VERSION 5.8 ;
BUSBITCHARS "[]" ;
DIVIDERCHAR "/" ;
UNITS
    DATABASE MICRONS 1000 ;
END UNITS

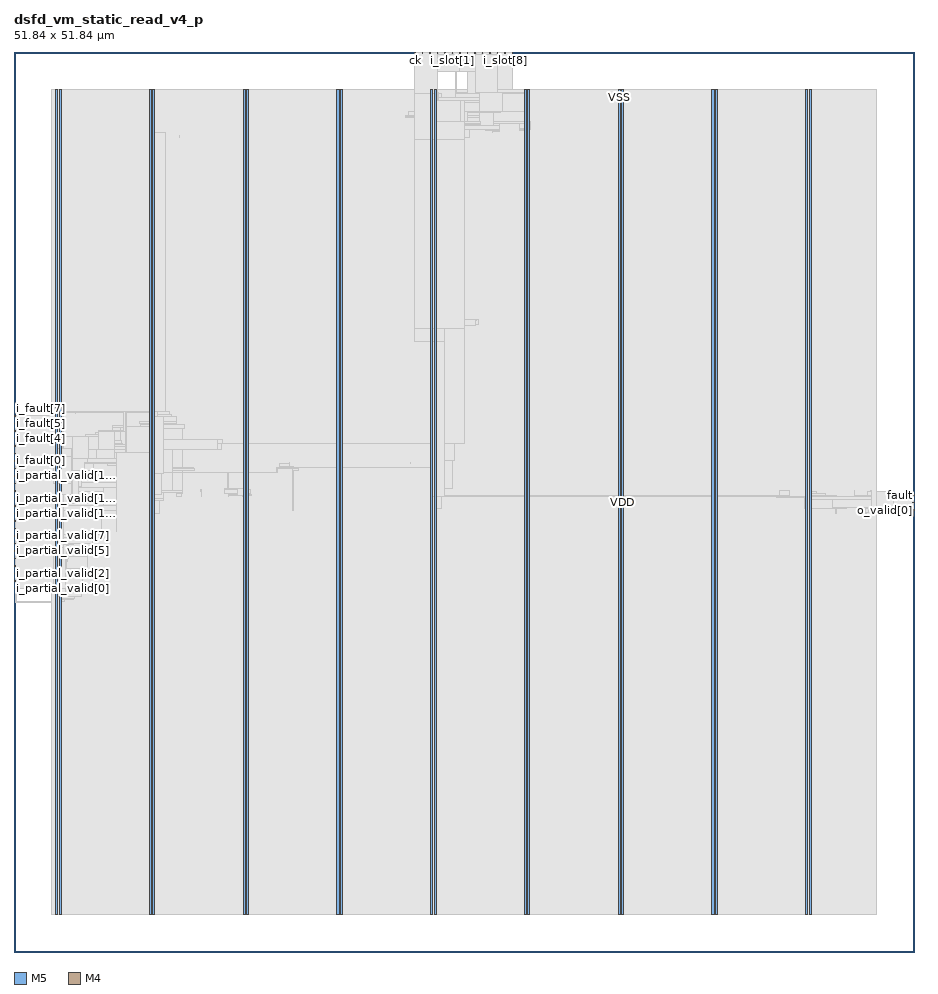
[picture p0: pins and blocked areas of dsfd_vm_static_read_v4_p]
MACRO dsfd_vm_static_read_v4_p
  FOREIGN dsfd_vm_static_read_v4_p 0 0 ;
  CLASS BLOCK ;
  SIZE 51.84 BY 51.84 ;
  PIN ck
    DIRECTION INPUT ;
    USE SIGNAL ;
    PORT
      LAYER M5 ;
        RECT  23.088 51.756 23.112 51.84 ;
    END
  END ck
  PIN fault
    DIRECTION OUTPUT ;
    USE SIGNAL ;
    PORT
      LAYER M4 ;
        RECT  51.756 26.304 51.84 26.328 ;
    END
  END fault
  PIN i_expected[0]
    DIRECTION INPUT ;
    USE SIGNAL ;
    PORT
      LAYER M5 ;
        RECT  23.952 51.756 23.976 51.84 ;
    END
  END i_expected[0]
  PIN i_expected[1]
    DIRECTION INPUT ;
    USE SIGNAL ;
    PORT
      LAYER M5 ;
        RECT  24.384 51.756 24.408 51.84 ;
    END
  END i_expected[1]
  PIN i_fault[0]
    DIRECTION INPUT ;
    USE SIGNAL ;
    PORT
      LAYER M4 ;
        RECT  0 27.84 0.084 27.864 ;
    END
  END i_fault[0]
  PIN i_fault[1]
    DIRECTION INPUT ;
    USE SIGNAL ;
    PORT
      LAYER M4 ;
        RECT  0 28.272 0.084 28.296 ;
    END
  END i_fault[1]
  PIN i_fault[2]
    DIRECTION INPUT ;
    USE SIGNAL ;
    PORT
      LAYER M4 ;
        RECT  0 28.704 0.084 28.728 ;
    END
  END i_fault[2]
  PIN i_fault[3]
    DIRECTION INPUT ;
    USE SIGNAL ;
    PORT
      LAYER M4 ;
        RECT  0 29.136 0.084 29.16 ;
    END
  END i_fault[3]
  PIN i_fault[4]
    DIRECTION INPUT ;
    USE SIGNAL ;
    PORT
      LAYER M4 ;
        RECT  0 29.568 0.084 29.592 ;
    END
  END i_fault[4]
  PIN i_fault[5]
    DIRECTION INPUT ;
    USE SIGNAL ;
    PORT
      LAYER M4 ;
        RECT  0 30 0.084 30.024 ;
    END
  END i_fault[5]
  PIN i_fault[6]
    DIRECTION INPUT ;
    USE SIGNAL ;
    PORT
      LAYER M4 ;
        RECT  0 30.432 0.084 30.456 ;
    END
  END i_fault[6]
  PIN i_fault[7]
    DIRECTION INPUT ;
    USE SIGNAL ;
    PORT
      LAYER M4 ;
        RECT  0 30.864 0.084 30.888 ;
    END
  END i_fault[7]
  PIN i_partial_valid[0]
    DIRECTION INPUT ;
    USE SIGNAL ;
    PORT
      LAYER M4 ;
        RECT  0 20.928 0.084 20.952 ;
    END
  END i_partial_valid[0]
  PIN i_partial_valid[10]
    DIRECTION INPUT ;
    USE SIGNAL ;
    PORT
      LAYER M4 ;
        RECT  0 25.248 0.084 25.272 ;
    END
  END i_partial_valid[10]
  PIN i_partial_valid[11]
    DIRECTION INPUT ;
    USE SIGNAL ;
    PORT
      LAYER M4 ;
        RECT  0 25.68 0.084 25.704 ;
    END
  END i_partial_valid[11]
  PIN i_partial_valid[12]
    DIRECTION INPUT ;
    USE SIGNAL ;
    PORT
      LAYER M4 ;
        RECT  0 26.112 0.084 26.136 ;
    END
  END i_partial_valid[12]
  PIN i_partial_valid[13]
    DIRECTION INPUT ;
    USE SIGNAL ;
    PORT
      LAYER M4 ;
        RECT  0 26.544 0.084 26.568 ;
    END
  END i_partial_valid[13]
  PIN i_partial_valid[14]
    DIRECTION INPUT ;
    USE SIGNAL ;
    PORT
      LAYER M4 ;
        RECT  0 26.976 0.084 27 ;
    END
  END i_partial_valid[14]
  PIN i_partial_valid[15]
    DIRECTION INPUT ;
    USE SIGNAL ;
    PORT
      LAYER M4 ;
        RECT  0 27.408 0.084 27.432 ;
    END
  END i_partial_valid[15]
  PIN i_partial_valid[1]
    DIRECTION INPUT ;
    USE SIGNAL ;
    PORT
      LAYER M4 ;
        RECT  0 21.36 0.084 21.384 ;
    END
  END i_partial_valid[1]
  PIN i_partial_valid[2]
    DIRECTION INPUT ;
    USE SIGNAL ;
    PORT
      LAYER M4 ;
        RECT  0 21.792 0.084 21.816 ;
    END
  END i_partial_valid[2]
  PIN i_partial_valid[3]
    DIRECTION INPUT ;
    USE SIGNAL ;
    PORT
      LAYER M4 ;
        RECT  0 22.224 0.084 22.248 ;
    END
  END i_partial_valid[3]
  PIN i_partial_valid[4]
    DIRECTION INPUT ;
    USE SIGNAL ;
    PORT
      LAYER M4 ;
        RECT  0 22.656 0.084 22.68 ;
    END
  END i_partial_valid[4]
  PIN i_partial_valid[5]
    DIRECTION INPUT ;
    USE SIGNAL ;
    PORT
      LAYER M4 ;
        RECT  0 23.088 0.084 23.112 ;
    END
  END i_partial_valid[5]
  PIN i_partial_valid[6]
    DIRECTION INPUT ;
    USE SIGNAL ;
    PORT
      LAYER M4 ;
        RECT  0 23.52 0.084 23.544 ;
    END
  END i_partial_valid[6]
  PIN i_partial_valid[7]
    DIRECTION INPUT ;
    USE SIGNAL ;
    PORT
      LAYER M4 ;
        RECT  0 23.952 0.084 23.976 ;
    END
  END i_partial_valid[7]
  PIN i_partial_valid[8]
    DIRECTION INPUT ;
    USE SIGNAL ;
    PORT
      LAYER M4 ;
        RECT  0 24.384 0.084 24.408 ;
    END
  END i_partial_valid[8]
  PIN i_partial_valid[9]
    DIRECTION INPUT ;
    USE SIGNAL ;
    PORT
      LAYER M4 ;
        RECT  0 24.816 0.084 24.84 ;
    END
  END i_partial_valid[9]
  PIN i_slot[0]
    DIRECTION INPUT ;
    USE SIGNAL ;
    PORT
      LAYER M5 ;
        RECT  24.816 51.756 24.84 51.84 ;
    END
  END i_slot[0]
  PIN i_slot[1]
    DIRECTION INPUT ;
    USE SIGNAL ;
    PORT
      LAYER M5 ;
        RECT  25.248 51.756 25.272 51.84 ;
    END
  END i_slot[1]
  PIN i_slot[2]
    DIRECTION INPUT ;
    USE SIGNAL ;
    PORT
      LAYER M5 ;
        RECT  25.68 51.756 25.704 51.84 ;
    END
  END i_slot[2]
  PIN i_slot[3]
    DIRECTION INPUT ;
    USE SIGNAL ;
    PORT
      LAYER M5 ;
        RECT  26.112 51.756 26.136 51.84 ;
    END
  END i_slot[3]
  PIN i_slot[4]
    DIRECTION INPUT ;
    USE SIGNAL ;
    PORT
      LAYER M5 ;
        RECT  26.544 51.756 26.568 51.84 ;
    END
  END i_slot[4]
  PIN i_slot[5]
    DIRECTION INPUT ;
    USE SIGNAL ;
    PORT
      LAYER M5 ;
        RECT  26.976 51.756 27 51.84 ;
    END
  END i_slot[5]
  PIN i_slot[6]
    DIRECTION INPUT ;
    USE SIGNAL ;
    PORT
      LAYER M5 ;
        RECT  27.408 51.756 27.432 51.84 ;
    END
  END i_slot[6]
  PIN i_slot[7]
    DIRECTION INPUT ;
    USE SIGNAL ;
    PORT
      LAYER M5 ;
        RECT  27.84 51.756 27.864 51.84 ;
    END
  END i_slot[7]
  PIN i_slot[8]
    DIRECTION INPUT ;
    USE SIGNAL ;
    PORT
      LAYER M5 ;
        RECT  28.272 51.756 28.296 51.84 ;
    END
  END i_slot[8]
  PIN i_slot[9]
    DIRECTION INPUT ;
    USE SIGNAL ;
    PORT
      LAYER M5 ;
        RECT  28.704 51.756 28.728 51.84 ;
    END
  END i_slot[9]
  PIN o_valid[0]
    DIRECTION OUTPUT ;
    USE SIGNAL ;
    PORT
      LAYER M4 ;
        RECT  51.756 25.44 51.84 25.464 ;
    END
  END o_valid[0]
  PIN o_valid[1]
    DIRECTION OUTPUT ;
    USE SIGNAL ;
    PORT
      LAYER M4 ;
        RECT  51.756 25.872 51.84 25.896 ;
    END
  END o_valid[1]
  PIN rst_n
    DIRECTION INPUT ;
    USE SIGNAL ;
    PORT
      LAYER M5 ;
        RECT  23.52 51.756 23.544 51.84 ;
    END
  END rst_n
  PIN VDD
    DIRECTION INOUT ;
    USE POWER ;
    PORT
      LAYER M5 ;
        RECT  45.792 2.151 45.912 49.689 ;
        RECT  40.392 2.151 40.512 49.689 ;
        RECT  34.992 2.151 35.112 49.689 ;
        RECT  29.592 2.151 29.712 49.689 ;
        RECT  24.192 2.151 24.312 49.689 ;
        RECT  18.792 2.151 18.912 49.689 ;
        RECT  13.392 2.151 13.512 49.689 ;
        RECT  7.992 2.151 8.112 49.689 ;
        RECT  2.592 2.151 2.712 49.689 ;
    END
  END VDD
  PIN VSS
    DIRECTION INOUT ;
    USE GROUND ;
    PORT
      LAYER M5 ;
        RECT  45.6 2.137 45.72 49.703 ;
        RECT  40.2 2.137 40.32 49.703 ;
        RECT  34.8 2.137 34.92 49.703 ;
        RECT  29.4 2.137 29.52 49.703 ;
        RECT  24 2.137 24.12 49.703 ;
        RECT  18.6 2.137 18.72 49.703 ;
        RECT  13.2 2.137 13.32 49.703 ;
        RECT  7.8 2.137 7.92 49.703 ;
        RECT  2.4 2.137 2.52 49.703 ;
    END
  END VSS
  # OT_OBS_CLOSED layer=M5 d_um=1.536 added=13
  OBS
    LAYER RVTN ;
     RECT  2.16 2.16 49.68 2.295 ;
     RECT  2.16 2.565 49.68 2.835 ;
     RECT  2.16 3.105 49.68 3.375 ;
     RECT  2.16 3.645 49.68 3.915 ;
     RECT  2.16 4.185 49.68 4.455 ;
     RECT  2.16 4.725 49.68 4.995 ;
     RECT  2.16 5.265 49.68 5.535 ;
     RECT  2.16 5.805 49.68 6.075 ;
     RECT  2.16 6.345 49.68 6.615 ;
     RECT  2.16 6.885 49.68 7.155 ;
     RECT  2.16 7.425 49.68 7.695 ;
     RECT  2.16 7.965 49.68 8.235 ;
     RECT  2.16 8.505 49.68 8.775 ;
     RECT  2.16 9.045 49.68 9.315 ;
     RECT  2.16 9.585 49.68 9.855 ;
     RECT  2.16 10.125 49.68 10.395 ;
     RECT  2.16 10.665 49.68 10.935 ;
     RECT  2.16 11.205 49.68 11.475 ;
     RECT  2.16 11.745 49.68 12.015 ;
     RECT  2.16 12.285 49.68 12.555 ;
     RECT  2.16 12.825 49.68 13.095 ;
     RECT  2.16 13.365 49.68 13.635 ;
     RECT  2.16 13.905 49.68 14.175 ;
     RECT  2.16 14.445 49.68 14.715 ;
     RECT  2.16 14.985 49.68 15.255 ;
     RECT  2.16 15.525 49.68 15.795 ;
     RECT  2.16 16.065 49.68 16.335 ;
     RECT  2.16 16.605 49.68 16.875 ;
     RECT  2.16 17.145 49.68 17.415 ;
     RECT  2.16 17.685 49.68 17.955 ;
     RECT  2.16 18.225 49.68 18.495 ;
     RECT  2.16 18.765 49.68 19.035 ;
     RECT  2.16 19.305 49.68 19.575 ;
     RECT  2.16 19.845 49.68 20.115 ;
     RECT  2.16 20.385 49.68 20.655 ;
     RECT  2.16 20.925 49.68 21.195 ;
     RECT  2.16 21.465 49.68 21.735 ;
     RECT  2.16 22.005 49.68 22.275 ;
     RECT  2.16 22.545 49.68 22.815 ;
     RECT  2.16 23.085 49.68 23.355 ;
     RECT  2.16 23.625 49.68 23.895 ;
     RECT  2.16 24.165 49.68 24.435 ;
     RECT  2.16 24.705 49.68 24.975 ;
     RECT  2.16 25.245 49.68 25.515 ;
     RECT  2.16 25.785 49.68 26.055 ;
     RECT  2.16 26.325 49.68 26.595 ;
     RECT  2.16 26.865 49.68 27.135 ;
     RECT  2.16 27.405 49.68 27.675 ;
     RECT  2.16 27.945 49.68 28.215 ;
     RECT  2.16 28.485 49.68 28.755 ;
     RECT  2.16 29.025 49.68 29.295 ;
     RECT  2.16 29.565 49.68 29.835 ;
     RECT  2.16 30.105 49.68 30.375 ;
     RECT  2.16 30.645 49.68 30.915 ;
     RECT  2.16 31.185 49.68 31.455 ;
     RECT  2.16 31.725 49.68 31.995 ;
     RECT  2.16 32.265 49.68 32.535 ;
     RECT  2.16 32.805 49.68 33.075 ;
     RECT  2.16 33.345 49.68 33.615 ;
     RECT  2.16 33.885 49.68 34.155 ;
     RECT  2.16 34.425 49.68 34.695 ;
     RECT  2.16 34.965 49.68 35.235 ;
     RECT  2.16 35.505 49.68 35.775 ;
     RECT  2.16 36.045 49.68 36.315 ;
     RECT  2.16 36.585 49.68 36.855 ;
     RECT  2.16 37.125 49.68 37.395 ;
     RECT  2.16 37.665 49.68 37.935 ;
     RECT  2.16 38.205 49.68 38.475 ;
     RECT  2.16 38.745 49.68 39.015 ;
     RECT  2.16 39.285 49.68 39.555 ;
     RECT  2.16 39.825 49.68 40.095 ;
     RECT  2.16 40.365 49.68 40.635 ;
     RECT  2.16 40.905 49.68 41.175 ;
     RECT  2.16 41.445 49.68 41.715 ;
     RECT  2.16 41.985 49.68 42.255 ;
     RECT  2.16 42.525 49.68 42.795 ;
     RECT  2.16 43.065 49.68 43.335 ;
     RECT  2.16 43.605 49.68 43.875 ;
     RECT  2.16 44.145 49.68 44.415 ;
     RECT  2.16 44.685 49.68 44.955 ;
     RECT  2.16 45.225 49.68 45.495 ;
     RECT  2.16 45.765 49.68 46.035 ;
     RECT  2.16 46.305 49.68 46.575 ;
     RECT  2.16 46.845 49.68 47.115 ;
     RECT  2.16 47.385 49.68 47.655 ;
     RECT  2.16 47.925 49.68 48.195 ;
     RECT  2.16 48.465 49.68 48.735 ;
     RECT  2.16 49.005 49.68 49.275 ;
     RECT  2.16 49.545 49.68 49.68 ;
    LAYER RVTP ;
     RECT  2.16 2.295 49.68 2.565 ;
     RECT  2.16 2.835 49.68 3.105 ;
     RECT  2.16 3.375 49.68 3.645 ;
     RECT  2.16 3.915 49.68 4.185 ;
     RECT  2.16 4.455 49.68 4.725 ;
     RECT  2.16 4.995 49.68 5.265 ;
     RECT  2.16 5.535 49.68 5.805 ;
     RECT  2.16 6.075 49.68 6.345 ;
     RECT  2.16 6.615 49.68 6.885 ;
     RECT  2.16 7.155 49.68 7.425 ;
     RECT  2.16 7.695 49.68 7.965 ;
     RECT  2.16 8.235 49.68 8.505 ;
     RECT  2.16 8.775 49.68 9.045 ;
     RECT  2.16 9.315 49.68 9.585 ;
     RECT  2.16 9.855 49.68 10.125 ;
     RECT  2.16 10.395 49.68 10.665 ;
     RECT  2.16 10.935 49.68 11.205 ;
     RECT  2.16 11.475 49.68 11.745 ;
     RECT  2.16 12.015 49.68 12.285 ;
     RECT  2.16 12.555 49.68 12.825 ;
     RECT  2.16 13.095 49.68 13.365 ;
     RECT  2.16 13.635 49.68 13.905 ;
     RECT  2.16 14.175 49.68 14.445 ;
     RECT  2.16 14.715 49.68 14.985 ;
     RECT  2.16 15.255 49.68 15.525 ;
     RECT  2.16 15.795 49.68 16.065 ;
     RECT  2.16 16.335 49.68 16.605 ;
     RECT  2.16 16.875 49.68 17.145 ;
     RECT  2.16 17.415 49.68 17.685 ;
     RECT  2.16 17.955 49.68 18.225 ;
     RECT  2.16 18.495 49.68 18.765 ;
     RECT  2.16 19.035 49.68 19.305 ;
     RECT  2.16 19.575 49.68 19.845 ;
     RECT  2.16 20.115 49.68 20.385 ;
     RECT  2.16 20.655 49.68 20.925 ;
     RECT  2.16 21.195 49.68 21.465 ;
     RECT  2.16 21.735 49.68 22.005 ;
     RECT  2.16 22.275 49.68 22.545 ;
     RECT  2.16 22.815 49.68 23.085 ;
     RECT  2.16 23.355 49.68 23.625 ;
     RECT  2.16 23.895 49.68 24.165 ;
     RECT  2.16 24.435 49.68 24.705 ;
     RECT  2.16 24.975 49.68 25.245 ;
     RECT  2.16 25.515 49.68 25.785 ;
     RECT  2.16 26.055 49.68 26.325 ;
     RECT  2.16 26.595 49.68 26.865 ;
     RECT  2.16 27.135 49.68 27.405 ;
     RECT  2.16 27.675 49.68 27.945 ;
     RECT  2.16 28.215 49.68 28.485 ;
     RECT  2.16 28.755 49.68 29.025 ;
     RECT  2.16 29.295 49.68 29.565 ;
     RECT  2.16 29.835 49.68 30.105 ;
     RECT  2.16 30.375 49.68 30.645 ;
     RECT  2.16 30.915 49.68 31.185 ;
     RECT  2.16 31.455 49.68 31.725 ;
     RECT  2.16 31.995 49.68 32.265 ;
     RECT  2.16 32.535 49.68 32.805 ;
     RECT  2.16 33.075 49.68 33.345 ;
     RECT  2.16 33.615 49.68 33.885 ;
     RECT  2.16 34.155 49.68 34.425 ;
     RECT  2.16 34.695 49.68 34.965 ;
     RECT  2.16 35.235 49.68 35.505 ;
     RECT  2.16 35.775 49.68 36.045 ;
     RECT  2.16 36.315 49.68 36.585 ;
     RECT  2.16 36.855 49.68 37.125 ;
     RECT  2.16 37.395 49.68 37.665 ;
     RECT  2.16 37.935 49.68 38.205 ;
     RECT  2.16 38.475 49.68 38.745 ;
     RECT  2.16 39.015 49.68 39.285 ;
     RECT  2.16 39.555 49.68 39.825 ;
     RECT  2.16 40.095 49.68 40.365 ;
     RECT  2.16 40.635 49.68 40.905 ;
     RECT  2.16 41.175 49.68 41.445 ;
     RECT  2.16 41.715 49.68 41.985 ;
     RECT  2.16 42.255 49.68 42.525 ;
     RECT  2.16 42.795 49.68 43.065 ;
     RECT  2.16 43.335 49.68 43.605 ;
     RECT  2.16 43.875 49.68 44.145 ;
     RECT  2.16 44.415 49.68 44.685 ;
     RECT  2.16 44.955 49.68 45.225 ;
     RECT  2.16 45.495 49.68 45.765 ;
     RECT  2.16 46.035 49.68 46.305 ;
     RECT  2.16 46.575 49.68 46.845 ;
     RECT  2.16 47.115 49.68 47.385 ;
     RECT  2.16 47.655 49.68 47.925 ;
     RECT  2.16 48.195 49.68 48.465 ;
     RECT  2.16 48.735 49.68 49.005 ;
     RECT  2.16 49.275 49.68 49.545 ;
    LAYER M1 ;
     RECT  2.16 2.151 49.68 49.689 ;
    LAYER M2 ;
     RECT  0.103 20.16 2.16 20.178 ;
     RECT  0.535 22.086 2.16 22.104 ;
     RECT  2.16 2.151 49.68 49.689 ;
     RECT  49.68 25.452 50.711 26.514 ;
    LAYER M3 ;
     RECT  2.415 2.143 2.505 2.413 ;
     RECT  7.815 2.143 7.905 2.413 ;
     RECT  13.215 2.143 13.305 2.413 ;
     RECT  18.615 2.143 18.705 2.413 ;
     RECT  24.015 2.143 24.105 2.413 ;
     RECT  29.415 2.143 29.505 2.413 ;
     RECT  34.815 2.143 34.905 2.413 ;
     RECT  40.215 2.143 40.305 2.413 ;
     RECT  45.615 2.143 45.705 2.413 ;
     RECT  2.415 2.413 2.697 20.191 ;
     RECT  2.412 20.191 2.898 20.317 ;
     RECT  2.412 20.317 3.402 20.353 ;
     RECT  2.412 20.353 3.51 20.461 ;
     RECT  2.412 20.461 3.906 20.731 ;
     RECT  2.34 20.731 3.906 20.923 ;
     RECT  2.304 20.923 3.906 21.001 ;
     RECT  0.108 20.155 0.126 21.389 ;
     RECT  2.304 21.001 3.942 22.081 ;
     RECT  2.304 22.081 4.23 22.775 ;
     RECT  2.34 22.775 4.23 22.981 ;
     RECT  2.34 22.981 4.374 23.053 ;
     RECT  0.54 22.081 0.558 23.117 ;
     RECT  2.34 23.053 4.482 23.161 ;
     RECT  2.34 23.161 4.518 23.515 ;
     RECT  2.304 23.515 4.518 23.863 ;
     RECT  2.304 23.863 4.95 24.061 ;
     RECT  7.815 2.413 8.097 25.285 ;
     RECT  49.068 25.285 49.086 25.321 ;
     RECT  2.304 24.061 5.058 25.447 ;
     RECT  5.904 24.205 5.922 25.447 ;
     RECT  47.34 25.249 47.358 25.519 ;
     RECT  45.615 2.413 45.897 25.531 ;
     RECT  24.015 2.413 24.297 25.555 ;
     RECT  49.068 25.321 49.194 25.555 ;
     RECT  47.16 25.519 47.97 25.591 ;
     RECT  49.068 25.555 49.374 25.591 ;
     RECT  2.304 25.447 5.922 25.745 ;
     RECT  7.815 25.285 8.37 25.987 ;
     RECT  45.54 25.531 45.897 26.059 ;
     RECT  47.16 25.591 49.374 26.059 ;
     RECT  7.815 25.987 8.586 26.095 ;
     RECT  43.956 26.203 43.974 26.221 ;
     RECT  45.54 26.059 49.374 26.237 ;
     RECT  45.615 26.237 49.374 26.249 ;
     RECT  9.612 26.221 9.63 26.257 ;
     RECT  13.215 2.413 13.497 26.257 ;
     RECT  43.884 26.221 43.974 26.257 ;
     RECT  43.884 26.257 44.658 26.285 ;
     RECT  45.615 26.249 47.394 26.285 ;
     RECT  48.384 26.249 49.374 26.285 ;
     RECT  12.348 26.257 12.366 26.293 ;
     RECT  13.14 26.257 13.497 26.293 ;
     RECT  12.348 26.293 13.662 26.333 ;
     RECT  9.36 26.257 9.63 26.401 ;
     RECT  12.348 26.333 13.626 26.401 ;
     RECT  45.615 26.285 46.746 26.429 ;
     RECT  7.815 26.095 8.622 26.491 ;
     RECT  9.36 26.401 9.702 26.491 ;
     RECT  45.615 26.429 46.206 26.519 ;
     RECT  49.176 26.285 49.374 26.519 ;
     RECT  50.688 25.435 50.706 26.519 ;
     RECT  2.304 25.745 5.13 26.527 ;
     RECT  10.8 26.221 10.818 26.527 ;
     RECT  10.764 26.527 10.818 26.528 ;
     RECT  48.384 26.285 48.402 26.555 ;
     RECT  49.356 26.519 49.374 26.555 ;
     RECT  7.815 26.491 9.702 26.591 ;
     RECT  44.1 26.285 44.658 26.591 ;
     RECT  12.132 26.401 13.626 26.627 ;
     RECT  7.815 26.591 8.37 26.663 ;
     RECT  10.764 26.528 10.782 26.663 ;
     RECT  13.14 26.627 13.626 26.663 ;
     RECT  24.015 25.555 24.606 26.671 ;
     RECT  12.132 26.627 12.366 26.699 ;
     RECT  2.268 26.527 5.13 26.761 ;
     RECT  5.904 25.745 5.922 26.761 ;
     RECT  12.348 26.699 12.366 26.765 ;
     RECT  13.14 26.663 13.497 26.789 ;
     RECT  2.268 26.761 5.922 27.059 ;
     RECT  2.268 27.059 4.842 27.329 ;
     RECT  2.268 27.329 4.59 27.707 ;
     RECT  9.108 26.591 9.702 27.715 ;
     RECT  16.056 25.411 16.074 27.715 ;
     RECT  9.108 27.715 10.314 27.751 ;
     RECT  9.108 27.751 10.422 27.869 ;
     RECT  16.056 27.715 16.398 27.869 ;
     RECT  15.12 27.595 15.138 27.877 ;
     RECT  16.056 27.869 16.074 27.877 ;
     RECT  9.108 27.869 10.314 27.905 ;
     RECT  2.268 27.707 3.294 27.917 ;
     RECT  15.12 27.877 16.074 27.917 ;
     RECT  15.264 27.917 16.074 27.941 ;
     RECT  5.904 27.059 5.922 28.021 ;
     RECT  4.068 27.707 4.59 28.111 ;
     RECT  5.4 28.021 5.922 28.111 ;
     RECT  15.264 27.941 15.858 28.139 ;
     RECT  2.268 27.917 3.222 28.175 ;
     RECT  4.068 28.111 5.922 28.175 ;
     RECT  15.84 28.139 15.858 28.175 ;
     RECT  22.824 28.111 22.842 28.211 ;
     RECT  24.015 26.671 25.254 28.291 ;
     RECT  4.248 28.175 5.922 28.445 ;
     RECT  7.815 26.663 8.097 28.759 ;
     RECT  5.76 28.445 5.922 28.789 ;
     RECT  7.416 28.759 8.097 28.795 ;
     RECT  7.308 28.795 8.097 28.993 ;
     RECT  9.108 27.905 9.702 28.993 ;
     RECT  5.76 28.789 6.462 29.101 ;
     RECT  7.308 28.993 9.702 29.101 ;
     RECT  5.76 29.101 9.702 29.255 ;
     RECT  5.76 29.255 6.246 29.291 ;
     RECT  2.268 28.175 3.186 29.363 ;
     RECT  11.7 28.921 11.97 29.461 ;
     RECT  5.76 29.291 6.21 29.489 ;
     RECT  4.248 28.445 4.734 29.497 ;
     RECT  11.7 29.461 12.006 29.501 ;
     RECT  11.7 29.501 11.718 29.525 ;
     RECT  2.412 29.363 3.186 29.569 ;
     RECT  4.14 29.497 4.734 29.659 ;
     RECT  2.412 29.569 3.33 29.693 ;
     RECT  4.14 29.659 4.878 29.795 ;
     RECT  4.716 29.795 4.878 29.939 ;
     RECT  4.86 29.939 4.878 30.035 ;
     RECT  5.76 29.489 6.138 30.037 ;
     RECT  2.412 29.693 2.697 30.065 ;
     RECT  7.308 29.255 9.702 30.181 ;
     RECT  5.652 30.037 6.138 30.235 ;
     RECT  5.652 30.235 6.354 30.335 ;
     RECT  6.336 30.335 6.354 30.371 ;
     RECT  7.308 30.181 9.846 30.371 ;
     RECT  7.308 30.371 9.702 30.407 ;
     RECT  2.415 30.065 2.697 30.415 ;
     RECT  7.308 30.407 9.378 30.415 ;
     RECT  2.415 30.415 2.826 30.461 ;
     RECT  7.2 30.415 9.378 30.569 ;
     RECT  7.815 30.569 9.378 30.839 ;
     RECT  7.815 30.839 9.054 30.947 ;
     RECT  6.048 31.081 6.066 31.099 ;
     RECT  7.815 30.947 8.946 31.109 ;
     RECT  3.528 30.991 3.546 31.133 ;
     RECT  5.868 31.099 6.066 31.133 ;
     RECT  5.868 31.133 5.886 31.145 ;
     RECT  24.015 28.291 25.362 35.035 ;
     RECT  24.015 35.035 25.938 35.075 ;
     RECT  26.568 36.085 26.586 36.121 ;
     RECT  26.568 36.121 26.766 36.125 ;
     RECT  26.604 36.125 26.766 36.419 ;
     RECT  24.015 35.075 25.362 38.515 ;
     RECT  24.015 38.515 25.578 46.921 ;
     RECT  9.54 46.921 9.558 47.039 ;
     RECT  7.815 31.109 8.73 47.219 ;
     RECT  27.54 47.191 27.558 47.281 ;
     RECT  27.54 47.281 27.954 47.317 ;
     RECT  29.415 2.413 29.697 47.317 ;
     RECT  29.124 47.317 29.697 47.353 ;
     RECT  24.015 46.921 26.262 47.389 ;
     RECT  27.144 47.317 27.954 47.389 ;
     RECT  29.124 47.353 29.754 47.425 ;
     RECT  24.015 47.389 27.954 47.579 ;
     RECT  24.015 47.579 26.874 47.659 ;
     RECT  23.508 47.659 26.874 47.731 ;
     RECT  27.612 47.579 27.954 47.731 ;
     RECT  29.088 47.425 29.754 47.731 ;
     RECT  23.22 47.731 26.874 47.849 ;
     RECT  27.612 47.731 29.754 47.849 ;
     RECT  23.22 47.849 26.838 48.091 ;
     RECT  22.536 48.091 26.838 48.191 ;
     RECT  22.716 48.191 26.838 48.389 ;
     RECT  27.612 47.849 29.697 48.389 ;
     RECT  28.008 48.389 29.697 48.413 ;
     RECT  23.364 48.389 26.838 48.929 ;
     RECT  23.472 48.929 26.838 49.037 ;
     RECT  23.508 49.037 26.838 49.073 ;
     RECT  23.544 49.073 26.838 49.199 ;
     RECT  2.415 30.461 2.697 49.427 ;
     RECT  7.815 47.219 8.097 49.427 ;
     RECT  13.215 26.789 13.497 49.427 ;
     RECT  18.615 2.413 18.897 49.427 ;
     RECT  28.152 48.413 29.697 49.427 ;
     RECT  34.815 2.413 35.097 49.427 ;
     RECT  40.215 2.413 40.497 49.427 ;
     RECT  45.615 26.519 45.897 49.427 ;
     RECT  23.544 49.199 24.642 49.469 ;
     RECT  25.452 49.199 26.802 49.469 ;
     RECT  23.544 49.469 24.462 49.505 ;
     RECT  23.652 49.505 24.462 49.517 ;
     RECT  25.452 49.469 26.622 49.517 ;
     RECT  28.152 49.427 29.505 49.517 ;
     RECT  23.652 49.517 24.105 49.541 ;
     RECT  27.612 49.531 27.63 49.577 ;
     RECT  2.415 49.427 2.505 49.697 ;
     RECT  7.815 49.427 7.905 49.697 ;
     RECT  13.215 49.427 13.305 49.697 ;
     RECT  18.615 49.427 18.705 49.697 ;
     RECT  23.976 49.541 24.105 49.697 ;
     RECT  29.415 49.517 29.505 49.697 ;
     RECT  34.815 49.427 34.905 49.697 ;
     RECT  40.215 49.427 40.305 49.697 ;
     RECT  45.615 49.427 45.705 49.697 ;
     RECT  23.976 49.697 23.994 49.853 ;
     RECT  25.452 49.517 25.47 50.765 ;
    LAYER M4 ;
     RECT  0.06 20.928 2.408 30.888 ;
     RECT  2.408 2.148 2.512 49.692 ;
     RECT  2.512 2.418 2.704 49.422 ;
     RECT  2.704 21.936 2.819 24.648 ;
     RECT  2.704 25.728 2.819 31.128 ;
     RECT  2.819 25.824 2.837 31.128 ;
     RECT  2.819 24.624 2.867 24.648 ;
     RECT  2.704 20.496 2.963 20.52 ;
     RECT  2.819 21.936 3.004 23.496 ;
     RECT  3.004 22.512 3.089 23.496 ;
     RECT  3.089 22.656 3.125 23.496 ;
     RECT  2.837 25.824 3.347 29.688 ;
     RECT  3.125 23.472 3.413 23.496 ;
     RECT  3.347 25.824 3.737 27.192 ;
     RECT  3.737 26.832 3.881 27.192 ;
     RECT  3.881 27.168 3.989 27.192 ;
     RECT  3.347 28.416 4.277 29.688 ;
     RECT  3.737 25.824 4.493 25.848 ;
     RECT  4.277 28.944 4.849 29.688 ;
     RECT  4.849 28.944 4.889 30.024 ;
     RECT  4.889 30 6.325 30.024 ;
     RECT  2.837 31.104 6.325 31.128 ;
     RECT  4.889 28.944 6.421 28.968 ;
     RECT  6.325 30 6.421 31.128 ;
     RECT  6.421 28.8 6.467 31.128 ;
     RECT  6.467 28.8 6.508 29.352 ;
     RECT  6.508 28.944 7.808 29.352 ;
     RECT  6.467 31.104 7.808 31.128 ;
     RECT  7.808 2.148 7.912 49.692 ;
     RECT  7.912 2.418 8.104 49.422 ;
     RECT  8.104 28.944 8.273 31.128 ;
     RECT  8.104 26.352 8.483 26.376 ;
     RECT  8.273 28.944 8.627 30.84 ;
     RECT  8.627 28.944 11.729 29.496 ;
     RECT  11.729 29.28 12.017 29.496 ;
     RECT  8.104 27.6 12.293 27.624 ;
     RECT  12.293 26.736 12.877 27.624 ;
     RECT  12.877 26.304 13.208 27.624 ;
     RECT  12.017 29.28 13.208 29.304 ;
     RECT  13.208 2.148 13.312 49.692 ;
     RECT  13.312 2.418 13.504 49.422 ;
     RECT  13.504 26.304 13.673 26.328 ;
     RECT  13.504 27.6 15.109 27.624 ;
     RECT  15.109 27.6 15.149 27.912 ;
     RECT  15.149 27.888 18.608 27.912 ;
     RECT  13.504 29.28 18.608 29.304 ;
     RECT  18.608 2.148 18.712 49.692 ;
     RECT  18.712 2.418 18.904 49.422 ;
     RECT  22.525 48.096 23.173 48.12 ;
     RECT  23.173 47.76 23.461 48.216 ;
     RECT  23.461 47.76 23.941 49.032 ;
     RECT  18.904 27.888 24.008 27.912 ;
     RECT  18.904 29.28 24.008 29.304 ;
     RECT  23.077 35.184 24.008 35.208 ;
     RECT  23.941 47.76 24.008 49.848 ;
     RECT  24.008 2.148 24.028 49.848 ;
     RECT  24.028 2.148 24.112 49.692 ;
     RECT  24.112 2.418 24.304 49.512 ;
     RECT  24.304 48.192 24.473 49.512 ;
     RECT  24.304 35.184 24.761 36.408 ;
     RECT  24.304 27.888 24.803 27.912 ;
     RECT  24.761 35.904 25.043 36.408 ;
     RECT  24.304 46.752 25.057 46.776 ;
     RECT  25.441 50.736 25.715 50.76 ;
     RECT  24.473 48.72 25.717 49.032 ;
     RECT  24.304 29.28 25.955 29.304 ;
     RECT  25.868 35.04 25.955 35.064 ;
     RECT  25.717 47.856 25.955 49.032 ;
     RECT  25.955 47.856 26.129 48.408 ;
     RECT  25.043 36.096 26.597 36.408 ;
     RECT  26.597 36.384 26.633 36.408 ;
     RECT  26.101 49.488 26.633 49.512 ;
     RECT  27.601 49.536 27.875 49.56 ;
     RECT  26.129 48.384 28.037 48.408 ;
     RECT  24.304 26.256 29.408 26.28 ;
     RECT  28.261 49.488 29.408 49.512 ;
     RECT  29.408 2.148 29.512 49.692 ;
     RECT  29.512 2.418 29.704 49.422 ;
     RECT  29.704 26.256 34.808 26.28 ;
     RECT  34.808 2.148 34.912 49.692 ;
     RECT  34.912 2.418 35.104 49.422 ;
     RECT  35.104 26.256 40.208 26.28 ;
     RECT  40.208 2.148 40.312 49.692 ;
     RECT  40.312 2.418 40.504 49.422 ;
     RECT  40.504 26.256 43.912 26.28 ;
     RECT  43.912 26.208 43.913 26.28 ;
     RECT  43.913 26.208 45.529 26.232 ;
     RECT  45.529 25.536 45.608 26.232 ;
     RECT  45.608 2.148 45.712 49.692 ;
     RECT  45.712 2.418 45.904 49.422 ;
     RECT  45.904 25.536 47.189 25.56 ;
     RECT  50.677 25.44 51.804 26.328 ;
    LAYER M5 ;
     RECT  2.4 2.137 2.52 2.151 ;
     RECT  7.8 2.137 7.92 2.151 ;
     RECT  13.2 2.137 13.32 2.151 ;
     RECT  18.6 2.137 18.72 2.151 ;
     RECT  24 2.137 24.12 2.151 ;
     RECT  29.4 2.137 29.52 2.151 ;
     RECT  34.8 2.137 34.92 2.151 ;
     RECT  40.2 2.137 40.32 2.151 ;
     RECT  45.6 2.137 45.72 2.151 ;
     RECT  2.4 2.151 2.712 20.485 ;
     RECT  2.4 20.485 2.952 20.965 ;
     RECT  2.304 20.965 2.952 22.883 ;
     RECT  2.304 22.883 2.856 23.315 ;
     RECT  24 2.151 24.312 26.245 ;
     RECT  2.4 23.315 2.856 26.341 ;
     RECT  7.8 2.151 8.112 26.341 ;
     RECT  13.2 2.151 13.512 26.725 ;
     RECT  2.4 26.341 3.336 26.965 ;
     RECT  7.8 26.341 8.472 27.589 ;
     RECT  12.336 26.725 13.512 27.635 ;
     RECT  2.304 26.965 3.336 28.547 ;
     RECT  2.4 28.547 3.336 28.979 ;
     RECT  6.432 28.789 6.456 30.275 ;
     RECT  7.8 27.589 8.616 30.851 ;
     RECT  24 26.245 24.792 35.173 ;
     RECT  23.088 35.173 24.792 35.893 ;
     RECT  25.92 29.269 25.944 35.893 ;
     RECT  23.088 35.893 25.944 46.787 ;
     RECT  25.92 46.787 25.944 47.845 ;
     RECT  25.728 47.845 25.944 49.043 ;
     RECT  23.088 46.787 24.312 49.477 ;
     RECT  29.4 2.151 29.712 49.477 ;
     RECT  28.272 49.477 29.712 49.525 ;
     RECT  2.4 28.979 2.712 49.689 ;
     RECT  7.8 30.851 8.112 49.689 ;
     RECT  13.2 27.635 13.512 49.689 ;
     RECT  18.6 2.151 18.912 49.689 ;
     RECT  27.84 49.525 29.712 49.689 ;
     RECT  34.8 2.151 35.112 49.689 ;
     RECT  40.2 2.151 40.512 49.689 ;
     RECT  45.6 2.151 45.912 49.689 ;
     RECT  2.4 49.689 2.52 49.703 ;
     RECT  7.8 49.689 7.92 49.703 ;
     RECT  13.2 49.689 13.32 49.703 ;
     RECT  18.6 49.689 18.72 49.703 ;
     RECT  27.84 49.689 29.52 49.703 ;
     RECT  34.8 49.689 34.92 49.703 ;
     RECT  40.2 49.689 40.32 49.703 ;
     RECT  45.6 49.689 45.72 49.703 ;
     RECT  26.112 49.477 26.568 50.725 ;
     RECT  23.088 49.477 24.408 51.792 ;
     RECT  25.68 50.725 26.568 51.792 ;
     RECT  27.84 49.703 28.728 51.792 ;
     RECT  6.456 28.789 7.8 30.275 ;
     RECT  24.792 29.269 25.92 35.893 ;
     RECT  24.312 46.787 25.92 47.845 ;
     RECT  24.312 47.845 25.728 49.043 ;
     RECT  24.312 49.043 24.408 49.477 ;
     RECT  26.568 49.525 27.84 51.708 ;
     RECT  24.408 50.725 25.68 51.708 ;
     RECT  24.456 51.708 24.768 51.792 ;
     RECT  24.888 51.708 25.2 51.792 ;
     RECT  25.32 51.708 25.632 51.792 ;
     RECT  26.616 51.708 26.928 51.792 ;
     RECT  27.048 51.708 27.36 51.792 ;
     RECT  27.48 51.708 27.792 51.792 ;
  END
END dsfd_vm_static_read_v4_p
END LIBRARY
